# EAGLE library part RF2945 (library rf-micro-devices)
RF TRANSCEIVER

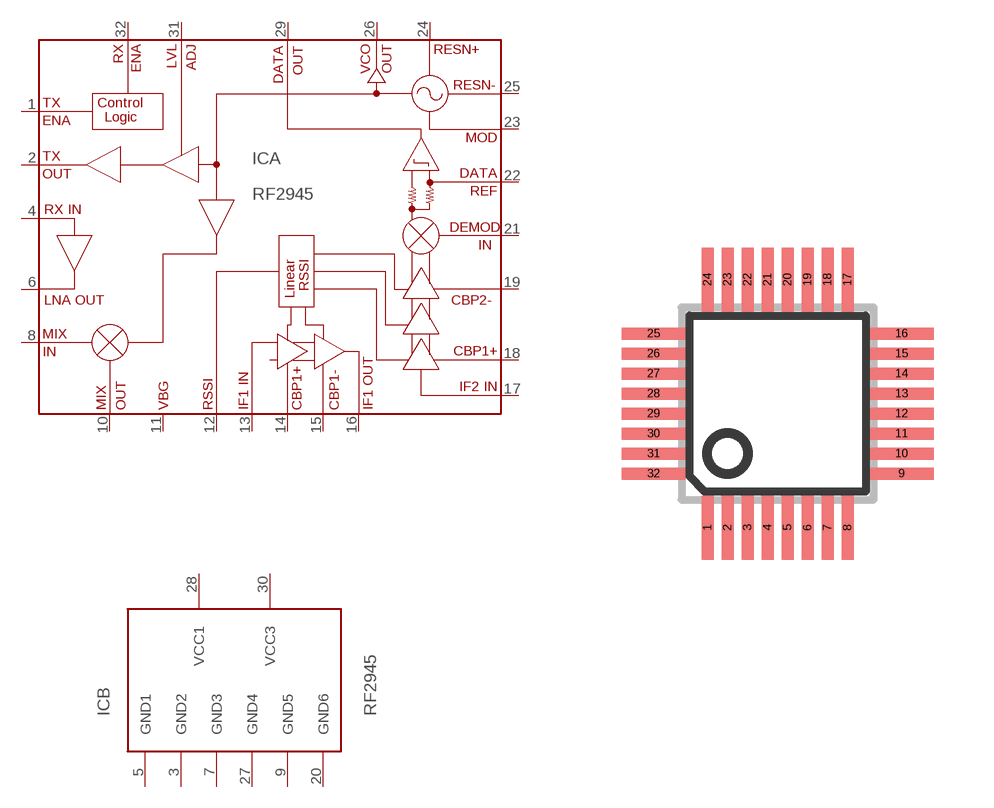
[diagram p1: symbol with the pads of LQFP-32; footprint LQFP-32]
Designator prefix IC; gates A=RF2945 B=RF2915P

## RF2945 (OC_FARNELL: unknown; OC_NEWARK: unknown)  [LQFP-32]
1  A:TX_EN  in
2  A:TX_OUT  pas
3  B:GND2  pas
4  A:RX_IN  pas
5  B:GND1  pas
6  A:LNA_OUT  oc
7  B:GND3  pas
8  A:MIX_IN  in
9  B:GND5  pas
10  A:MIX_OUT  out
11  A:VBG  pas
12  A:RSSI  out
13  A:IF1_IN  pas
14  A:CBPI+  pas
15  A:CBP1-  pas
16  A:IF1_OUT  pas
17  A:IF2_IN  pas
18  A:CBP2+  pas
19  A:CBP2-  pas
20  B:GND6  pas
21  A:DEMOD_IN  pas
22  A:DATA_REF  pas
23  A:MOD_IN  pas
24  A:RESNTR+  pas
25  A:RESNTR-  pas
26  A:VCD_OUT  pas
27  B:GND4  pas
28  B:VCC1  pas
29  A:DATA_OUT  out
30  B:VCC3  pas
31  A:LVLADJ  pas
32  A:RX_EN  in

## Footprint LQFP-32 (pad centres in mm)
Quad FLat Pack RFMicro Device TQFP / LQFP-32, see IPC-SQR.LBR SQFP 5x5-32
smd 0.3 x 1.6: 1 -1.75,-3.1; 2 -1.25,-3.1; 3 -0.75,-3.1; 4 -0.25,-3.1; 5 0.25,-3.1; 6 0.75,-3.1; 7 1.25,-3.1; 8 1.75,-3.1; 17 1.75,3.1; 18 1.25,3.1; 19 0.75,3.1; 20 0.25,3.1; 21 -0.25,3.1; 22 -0.75,3.1; 23 -1.25,3.1; 24 -1.75,3.1
smd 1.6 x 0.3: 9 3.1,-1.75; 10 3.1,-1.25; 11 3.1,-0.75; 12 3.1,-0.25; 13 3.1,0.25; 14 3.1,0.75; 15 3.1,1.25; 16 3.1,1.75; 25 -3.1,1.75; 26 -3.1,1.25; 27 -3.1,0.75; 28 -3.1,0.25; 29 -3.1,-0.25; 30 -3.1,-0.75; 31 -3.1,-1.25; 32 -3.1,-1.75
